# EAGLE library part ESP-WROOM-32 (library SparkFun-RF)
ESP-WROOM-32D - trace antenna (includes keepout) ESP-WROOM-32U - U.FL antenna connector Includes both "standard" footprints and "narrow" version (for use with tighter layouts).

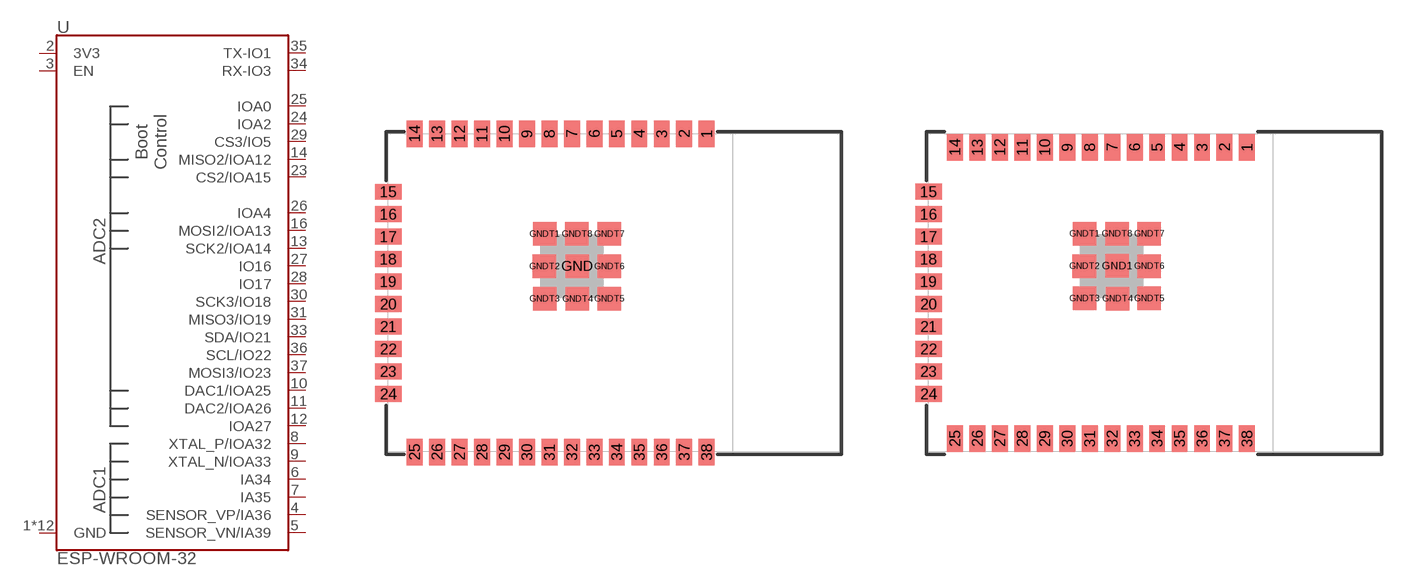
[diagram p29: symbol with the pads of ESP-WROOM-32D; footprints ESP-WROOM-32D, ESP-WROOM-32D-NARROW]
Designator prefix U

## ESP-WROOM-3232D (PROD_ID: IC-13849)  [ESP-WROOM-32D]
1  GND
2  3V3
3  EN
4  SENSOR_VP/IA36
5  SENSOR_VN/IA39
6  IA34
7  IA35
8  XTAL_P/IOA32
9  XTAL_N/IOA33
10  DAC1/IOA25
11  DAC2/IOA26
12  IOA27
13  SCK2/IOA14
14  MISO2/IOA12
15  GND
16  MOSI2/IOA13
23  CS2/IOA15
24  IOA2
25  IOA0
26  IOA4
27  IO16
28  IO17
29  CS3/IO5
30  SCK3/IO18
31  MISO3/IO19
33  SDA/IO21
34  RX-IO3
35  TX-IO1
36  SCL/IO22
37  MOSI3/IO23
38  GND
GND  GND
GNDT1  GND
GNDT2  GND
GNDT3  GND
GNDT4  GND
GNDT5  GND
GNDT6  GND
GNDT7  GND
GNDT8  GND

## ESP-WROOM-3232D-NARROW (PROD_ID: IC-13849)  [ESP-WROOM-32D-NARROW]
1  GND
2  3V3
3  EN
4  SENSOR_VP/IA36
5  SENSOR_VN/IA39
6  IA34
7  IA35
8  XTAL_P/IOA32
9  XTAL_N/IOA33
10  DAC1/IOA25
11  DAC2/IOA26
12  IOA27
13  SCK2/IOA14
14  MISO2/IOA12
15  GND
16  MOSI2/IOA13
23  CS2/IOA15
24  IOA2
25  IOA0
26  IOA4
27  IO16
28  IO17
29  CS3/IO5
30  SCK3/IO18
31  MISO3/IO19
33  SDA/IO21
34  RX-IO3
35  TX-IO1
36  SCL/IO22
37  MOSI3/IO23
38  GND
GND1  GND
GNDT1  GND
GNDT2  GND
GNDT3  GND
GNDT4  GND
GNDT5  GND
GNDT6  GND
GNDT7  GND
GNDT8  GND

## ESP-WROOM-32EU-NARROW (PROD_ID: IC-15442)  [ESP-WROOM-32EU-NARROW]
Pads as for ESP-WROOM-32D

## ESP-WROOM-32EU (PROD_ID: IC-15442)  [ESP-WROOM-32EU]
Pads as for ESP-WROOM-32D

## Footprint ESP-WROOM-32D (pad centres in mm)
ESP-WROOM-32D This version of the module contains an onboard trace-antenna connector. It is virtually identical to the onboard u.FL version (ESP32-WROOM-32U), except it is slightly longer and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
smd 0.9 x 1.5: 1 7.7,9; 2 6.43,9; 3 5.16,9; 4 3.89,9; 5 2.62,9; 6 1.35,9; 7 0.08,9; 8 -1.19,9; 9 -2.46,9; 10 -3.73,9; 11 -5,9; 12 -6.27,9; 13 -7.54,9; 14 -8.81,9; 25 -8.81,-9; 26 -7.54,-9; 27 -6.27,-9; 28 -5,-9; 29 -3.73,-9; 30 -2.46,-9; 31 -1.19,-9; 32 0.08,-9; 33 1.35,-9; 34 2.62,-9; 35 3.89,-9; 36 5.16,-9; 37 6.43,-9; 38 7.7,-9
smd 1.5 x 0.9: 15 -10.3,5.715; 16 -10.3,4.445; 17 -10.3,3.175; 18 -10.3,1.905; 19 -10.3,0.635; 20 -10.3,-0.635; 21 -10.3,-1.905; 22 -10.3,-3.175; 23 -10.3,-4.445; 24 -10.3,-5.715
smd 1.33 x 1.33: GND 0.379,1.515; GNDT1 -1.46,3.33; GNDT2 -1.47,1.5; GNDT3 -1.46,-0.33; GNDT4 0.4,-0.34; GNDT5 2.2,-0.33; GNDT6 2.2,1.5; GNDT7 2.2,3.33; GNDT8 0.37,3.33

## Footprint ESP-WROOM-32D-NARROW (pad centres in mm)
ESP-WROOM-32D This version of the module contains an onboard trace-antenna connector. It is virtually identical to the onboard u.FL version (ESP32-WROOM-32U), except it is slightly longer and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
smd 0.9 x 1.5: 1 6.43,8.238; 2 5.16,8.238; 3 3.89,8.238; 4 2.62,8.238; 5 1.35,8.238; 6 0.08,8.238; 7 -1.19,8.238; 8 -2.46,8.238; 9 -3.73,8.238; 10 -5,8.238; 11 -6.27,8.238; 12 -7.54,8.238; 13 -8.81,8.238; 14 -10.08,8.238; 25 -10.08,-8.238; 26 -8.81,-8.238; 27 -7.54,-8.238; 28 -6.27,-8.238; 29 -5,-8.238; 30 -3.73,-8.238; 31 -2.46,-8.238; 32 -1.19,-8.238; 33 0.08,-8.238; 34 1.35,-8.238; 35 2.62,-8.238; 36 3.89,-8.238; 37 5.16,-8.238; 38 6.43,-8.238
smd 1.5 x 0.9: 15 -11.57,5.715; 16 -11.57,4.445; 17 -11.57,3.175; 18 -11.57,1.905; 19 -11.57,0.635; 20 -11.57,-0.635; 21 -11.57,-1.905; 22 -11.57,-3.175; 23 -11.57,-4.445; 24 -11.57,-5.715
smd 1.33 x 1.33: GND1 -0.912,1.531; GNDT1 -2.751,3.346; GNDT2 -2.761,1.516; GNDT3 -2.751,-0.314; GNDT4 -0.891,-0.324; GNDT5 0.909,-0.314; GNDT6 0.909,1.516; GNDT7 0.909,3.346; GNDT8 -0.921,3.346

## Footprint ESP-WROOM-32EU-NARROW (pad centres in mm)
ESP-WROOM-32EU This version of the module contains the u.FL antenna connector. It is virtually identical to the onboard trace-antenna version (ESP32-WROOM-32D), except it is slightly shorter and does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
smd 0.9 x 1.5: 1 6.43,8.238; 2 5.16,8.238; 3 3.89,8.238; 4 2.62,8.238; 5 1.35,8.238; 6 0.08,8.238; 7 -1.19,8.238; 8 -2.46,8.238; 9 -3.73,8.238; 10 -5,8.238; 11 -6.27,8.238; 12 -7.54,8.238; 13 -8.81,8.238; 14 -10.08,8.238; 25 -10.08,-8.238; 26 -8.81,-8.238; 27 -7.54,-8.238; 28 -6.27,-8.238; 29 -5,-8.238; 30 -3.73,-8.238; 31 -2.46,-8.238; 32 -1.19,-8.238; 33 0.08,-8.238; 34 1.35,-8.238; 35 2.62,-8.238; 36 3.89,-8.238; 37 5.16,-8.238; 38 6.43,-8.238
smd 1.5 x 0.9: 15 -11.57,5.715; 16 -11.57,4.445; 17 -11.57,3.175; 18 -11.57,1.905; 19 -11.57,0.635; 20 -11.57,-0.635; 21 -11.57,-1.905; 22 -11.57,-3.175; 23 -11.57,-4.445; 24 -11.57,-5.715
smd 1.33 x 1.33: GND -0.961,1.515; GNDT1 -2.8,3.33; GNDT2 -2.81,1.5; GNDT3 -2.8,-0.33; GNDT4 -0.94,-0.34; GNDT5 0.86,-0.33; GNDT6 0.86,1.5; GNDT7 0.86,3.33; GNDT8 -0.97,3.33

## Footprint ESP-WROOM-32EU (pad centres in mm)
ESP-WROOM-32EU This version of the module contains the u.FL antenna connector. It is virtually identical to the onboard trace-antenna version (ESP32-WROOM-32D), except it is slightly shorter and does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
smd 0.9 x 1.5: 1 7.7,9; 2 6.43,9; 3 5.16,9; 4 3.89,9; 5 2.62,9; 6 1.35,9; 7 0.08,9; 8 -1.19,9; 9 -2.46,9; 10 -3.73,9; 11 -5,9; 12 -6.27,9; 13 -7.54,9; 14 -8.81,9; 25 -8.81,-9; 26 -7.54,-9; 27 -6.27,-9; 28 -5,-9; 29 -3.73,-9; 30 -2.46,-9; 31 -1.19,-9; 32 0.08,-9; 33 1.35,-9; 34 2.62,-9; 35 3.89,-9; 36 5.16,-9; 37 6.43,-9; 38 7.7,-9
smd 1.5 x 0.9: 15 -10.3,5.715; 16 -10.3,4.445; 17 -10.3,3.175; 18 -10.3,1.905; 19 -10.3,0.635; 20 -10.3,-0.635; 21 -10.3,-1.905; 22 -10.3,-3.175; 23 -10.3,-4.445; 24 -10.3,-5.715
smd 1.33 x 1.33: GND 0.339,1.515; GNDT1 -1.5,3.33; GNDT2 -1.51,1.5; GNDT3 -1.5,-0.33; GNDT4 0.36,-0.34; GNDT5 2.16,-0.33; GNDT6 2.16,1.5; GNDT7 2.16,3.33; GNDT8 0.33,3.33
